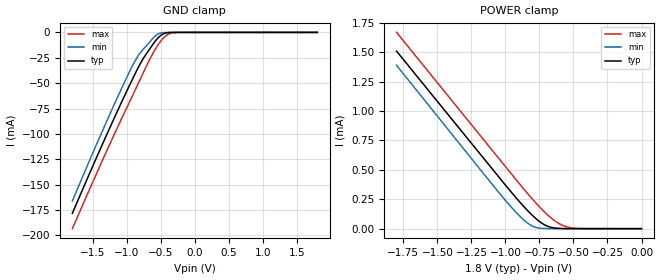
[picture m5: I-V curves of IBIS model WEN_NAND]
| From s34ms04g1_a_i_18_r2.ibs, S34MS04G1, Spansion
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|   Model WEN_NAND
[Model]   WEN_NAND
Model_type   Input
Vinl = 0.360V
Vinh = 1.440V
| variable   typ   min   max
C_comp   2.20pF   1.98pF   2.64pF
| variable   typ   min   max
[Temperature Range]  25.00   -30.00   85.00
[Voltage Range]   1.800   1.700   1.950
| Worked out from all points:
|   GND clamp passes 1 mA (typ) near -0.44 V on its own axis
|   POWER clamp passes 1 mA (typ) near -1.44 V on its own axis
[GND_clamp]
| voltage   I(typ)   I(min)   I(max)
-1.8V     -178.1mA   -166mA     -193.3mA
-1.296V   -100.8mA   -87.54mA   -116.8mA
-1.08V    -69.14mA   -55.62mA   -85.41mA
-900mV    -43.74mA   -30.61mA   -59.98mA
-828mV    -34.04mA   -22.44mA   -49.77mA
-756mV    -25.46mA   -16.37mA   -39.46mA
-612mV    -11.31mA   -5.42mA    -20.15mA
-504mV    -3.107mA   -584.6uA   -8.76mA
-432mV    -701.8uA   -55.31uA   -3.654mA
-360mV    -93.96uA   -2.943uA   -1.017mA
-252mV    -2.155uA   -17.44nA   -71.48uA
1.8V      140.8pA    79.49pA    15.92nA
[POWER_clamp]
| voltage   I(typ)   I(min)   I(max)
-1.8V     1.507mA    1.387mA    1.667mA
-1.026V   406.7uA    275.8uA    564.4uA
-900mV    233.3uA    112.2uA    385.2uA
-828mV    142.9uA    39.6uA     286uA
-774mV    83.47uA    9.835uA    215.4uA
-702mV    26.5uA     788.5nA    129.7uA
-630mV    4.493uA    62.15nA    60.6uA
-558mV    538.1nA    3.703nA    18.69uA
-450mV    16.7nA     132.3pA    1.525uA
0V        0A         0A         0A
